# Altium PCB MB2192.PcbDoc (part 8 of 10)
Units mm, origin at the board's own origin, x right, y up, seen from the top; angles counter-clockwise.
Board outline 127 x 97 mm, 6 copper layers (Top Layer, Signal Layer 1, Signal Layer 2, Signal Layer 3, Signal Layer 4, Bottom Layer), stack 1.557 mm thick; 560 components, 463 nets, 2347 pads, 1688 vias.
Unrouted connection lines stored in the file: 3.

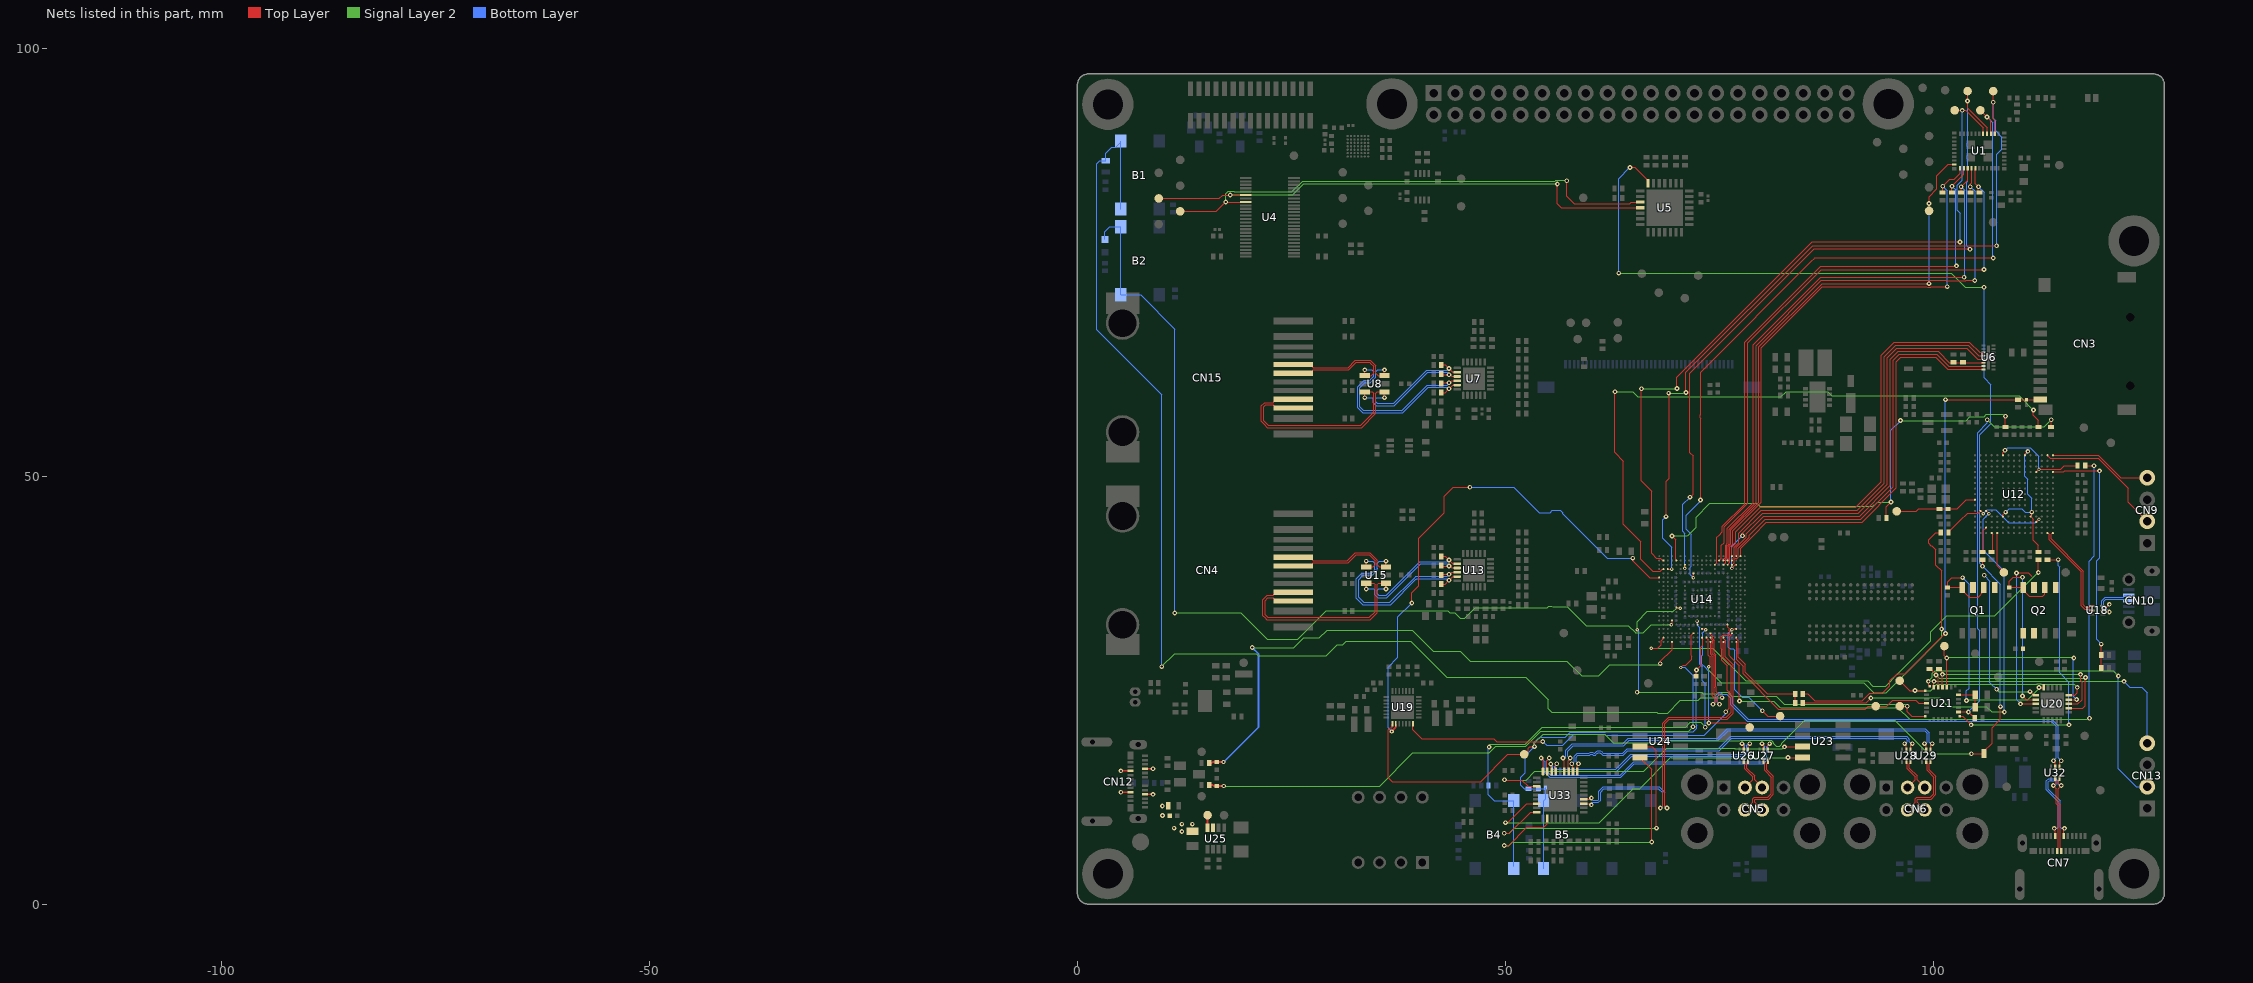
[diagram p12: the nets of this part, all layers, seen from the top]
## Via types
v1: diameter 0.55, hole 0.25, Top Layer to Bottom Layer, 1314 vias
v2: diameter 0.4, hole 0.2, Top Layer to Bottom Layer, 263 vias
v3: diameter 0.5, hole 0.2, Top Layer to Bottom Layer, 51 vias
v4: diameter 0.26, hole 0.1, Top Layer to Signal Layer 1, tented both sides, 29 vias
v5: diameter 0.4, hole 0.2, Top Layer to Bottom Layer, tented both sides, 19 vias
v6: diameter 0.5, hole 0.25, Top Layer to Bottom Layer, 12 vias

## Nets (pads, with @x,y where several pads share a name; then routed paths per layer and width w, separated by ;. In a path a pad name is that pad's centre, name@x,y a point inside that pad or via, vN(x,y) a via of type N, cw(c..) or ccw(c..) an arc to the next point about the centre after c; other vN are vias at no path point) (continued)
NRST: B5.1 B5.2 C118.1 C223.2 D4.2 R88.2 R180.1 TP29.1 U5.14 U14.Y11 U19.1 U37.1 | length 249.9
  Top Layer w0.075: 72.7,27.725 72.85,27.875 72.85,30.019 73.059,30.229 73.059,30.923 72.999,30.983 72.999,31.126 U14.Y11@72.975,31.15
  Top Layer w0.1: U19.1@36.8,21.1 36.8,20.684 36.741,20.625 36.525,20.625 36.3,20.4 36.3,14.781 36.756,14.325 47.125,14.325 50.3,17.5 TP29.1@52.15,17.5 ; TP29.1@52.2,17.5 52.65,17.95 52.65,18.225 52.825,18.4 v1(53.4,18.4) v1@53.425,18.4 ; v1(64.55,86.075) 65.1,86.075 66.675,84.5 U5.14@66.675,84.225 ; C118.1@72.325,26.625 v1(72.325,27.35) 72.7,27.725 ; v1(104.45,17.575) 105.92,17.575 105.92,17.845 106.875,18.8 106.875,20.6 107.85,21.575 v1(107.85,23.075) ; v1(105.75,39.475) R88.2@105.75,40.25
  Signal Layer 2 w0.1: v1@53.4,18.425 53.4,18.85 54.4,19.85 61.625,19.85 62.625,18.85 67.775,18.85 68.025,19.1 77.399,19.1 77.474,19.175 81.051,19.175 81.3,18.926 81.3,18.804 81.678,18.426 82.03,18.426 82.279,18.675 82.279,18.784 84.97,21.475 95.5,21.475 99.4,17.575 v1(104.45,17.575) ; v1(63.25,73.725) 102.075,73.725 103.725,72.075 v1(105.925,72.075)
  Bottom Layer w0.1: B5.2@54.475,4.15 B5.1@54.475,12.1 54.692,12.317 U37.1@54.692,13.602 ; U37.1@54.692,13.625 U37.1@54.692,13.602 ; v1(63.25,73.725) 63.25,84.775 v1(64.55,86.075) ; v1(72.325,27.35) 72.325,23.759 72.3,23.734 72.3,20.951 72.35,20.901 72.35,20.549 72.3,20.499 72.3,20.475 71.975,20.15 61.725,20.15 61.65,20.075 57.6,20.075 57.025,19.5 54.025,19.5 53.4,18.875 v1(53.4,18.4) 52.349,17.349 52.349,15.349 51.8,14.8 51.8,13.9 52.213,13.487 R180.1@52.692,13.487 C223.2@53.867,13.487 54.577,13.487 U37.1@54.692,13.602 ; v1(105.925,72.075) 105.925,61.5 106.725,60.7 106.725,56.15 105.422,54.847 105.422,39.803 v1(105.75,39.475) 107.85,37.375 v1(107.85,23.075)
PA13: B2.1 B2.2 LD4.2 U14.T4 | length 115.8
  Top Layer w0.09: v2@69.475,32.725 U14.T4@69.475,33.15
  Signal Layer 2 w0.09: 65.175,31.75 65.2,31.725 66.125,31.725 67.05,32.65 v2(69.4,32.65)
  Signal Layer 2 w0.1: v1(11.375,34.025) 11.4,34.05 19.075,34.05 22.15,30.975 25.75,30.975 29.05,34.275 43.261,34.275 43.486,34.05 44.058,34.05 44.708,33.4 45.225,33.4 46.475,34.65 54.9,34.65 55.077,34.827 55.429,34.827 55.53,34.725 57.25,34.725 59.425,32.55 64.375,32.55 65.175,31.75
  Bottom Layer w0.1: LD4.2@3.205,77.663 3.205,78.58 3.763,79.138 B2.1@5.055,79.138 B2.2@5.055,71.188 7.372,71.188 11.375,67.185 v1(11.375,34.025)
PA14: B1.1 B1.2 LD3.2 U14.W13 | length 154
  Top Layer w0.075: U14.W13@73.975,31.65 73.998,31.627 73.998,31.502 74.225,31.275 74.225,30.987 74.39,30.822 74.39,29.335 74.595,29.13 74.595,27.916 74.608,27.903 74.608,27.725
  Top Layer w0.1: 74.608,27.725 74.608,26.955 74.595,26.942 74.595,25.408 74.613,25.39 74.613,24.837 v1(75.325,24.125)
  Signal Layer 2 w0.1: v1@9.85,27.775 9.875,27.775 11.35,29.25 20.879,29.25 21.129,29 29.058,29 30.358,30.3 30.999,30.3 31.424,30.725 38.925,30.725 43.15,26.5 52.367,26.5 55,23.867 55,22.8 55.4,22.4 67.7,22.4 67.775,22.325 68.95,22.325 70.451,23.826 72.551,23.826 72.85,24.125 v1(75.325,24.125)
  Bottom Layer w0.1: B1.2@5.055,81.213 B1.1@5.055,89.038 ; B1.1@5.055,89.163 B1.1@5.055,89.038 ; v1(9.85,27.75) 9.85,59.525 2.275,67.1 2.275,86.517 2.621,86.863 LD3.2@3.305,86.863 3.305,87.73 4.013,88.438 4.455,88.438 B1.1@5.055,89.038
PF8_WKUP: U14.F1 U19.2 | length 61.8
  Top Layer w0.075: 65.175,39.85 66.875,38.15 U14.F1@67.975,38.15
  Top Layer w0.1: v1(39.075,35.175) 39.075,36.375 39.9,37.2 39.9,42.775 42.875,45.75 42.875,47.642 43.936,48.702 v1(45.852,48.702) ; v1(64.875,40.425) 64.875,40.15 65.175,39.85
  Top Layer w0.15: v3(36.725,20.175) 37.191,20.641 37.191,21.091 U19.2@37.2,21.1
  Bottom Layer w0.1: v3(36.725,20.175) 36.3,20.6 36.3,27.7 37.45,28.85 37.45,33.55 v1(39.075,35.175) ; v1(45.852,48.702) 50.998,48.702 53.95,45.75 55.225,45.75 55.475,46 56.426,46 56.675,45.751 56.675,45.625 61.875,40.425 v1(64.875,40.425)
PH4: R188.2 R189.2 U14.Y19 | length 12.4
  Top Layer w0.075: U14.Y19@76.975,31.15 76.986,31.139 76.986,30.989 77.225,30.75 77.225,30.296 77.225,28.825 77.638,28.412 78.05,28 78.05,27.725
  Top Layer w0.1: 78.05,27.725 78.05,27.1 80.582,24.568 R188.2@83.85,24.568 R189.2@83.85,23.518
PRTPWR1: U23.3 U33.12 | length 40.6
  Top Layer w0.1: v1(49.9,14.525) 49.945,14.5 50.345,14.5 ccw(c50.55,14.873) 50.568,14.448 51.817,14.5 51.9,14.5 51.929,14.471 52.65,13.75 U33.12@53.65,13.75 ; v1(82.604,18.376) 84.666,18.376 84.715,18.425 U23.3@84.725,18.415
  Signal Layer 2 w0.1: v1(49.9,14.525) 49.975,14.45 50.474,14.45 50.535,14.448 ccw(c50.55,14.873) 50.557,14.448 52.429,14.479 53.45,15.5 66.175,15.5 68.875,18.2 76.778,18.2 76.803,18.176 82.326,18.176 82.526,18.376 v1(82.604,18.376)
PRTPWR2: U23.4 U33.16 | length 42.4
  Top Layer w0.1: v1(50.025,9.525) 50.3,9.525 52.525,11.75 U33.16@53.65,11.75 ; v1(83.029,17.126) 84.696,17.126 84.72,17.15 U23.4@84.725,17.145
  Signal Layer 2 w0.1: v1(50.025,9.525) 60.95,9.525 64.925,13.5 65.7,13.5 69.35,17.15 69.374,17.126 v1(83.029,17.126)
PRTPWR3: U24.3 U33.18 | length 34
  Top Layer w0.1: v1(49.875,8.275) 50.475,8.275 52.95,10.75 U33.18@53.65,10.75 ; U24.3@65.725,18.39 67.185,18.39 67.65,17.925 v1(67.65,8.875)
  Signal Layer 2 w0.1: v1(49.875,8.275) 50.425,8.275 51.025,8.875 v1(67.65,8.875)
PRTPWR4: U24.4 U33.20 | length 34.5
  Top Layer w0.1: v1(49.875,6.85) 50.375,6.85 52.525,9 54.5,9 54.9,9.4 U33.20@54.9,10 ; U24.4@65.725,17.12 67.1,15.745 v1(67.1,7.25)
  Signal Layer 2 w0.1: v1(49.875,6.85) 50.375,6.85 50.775,7.25 v1(67.1,7.25)
PWR_LP: TP61.1 U14.V19 | length 15.1
  Top Layer w0.09: v2@76.55,32.15 U14.V19@76.975,32.15
  Top Layer w0.1: v1(80.025,22.6) 80.65,21.975 TP61.1@82.1,21.975 TP61.1@82.475,21.975
  Bottom Layer w0.09: v2(76.475,32.075) 76.059,31.659 76.059,31.462 76.059,30.041 76.275,29.825 76.625,29.825 76.814,29.636 76.814,27.725 76.814,25.061 77.684,24.191 77.7,24.175
  Bottom Layer w0.1: 77.684,24.191 78.434,24.191 v1(80.025,22.6)
PWR_NJTRST: TP63.1 U14.V11 | length 17.2
  Top Layer w0.1: U14.V11@72.975,32.15 v2@73.4,32.15 ; v1(73.775,21.175) 78.025,21.175 TP63.1@78.55,20.65 TP63.1@78.55,20.3
  Bottom Layer w0.09: v2(73.425,32.075) 73.075,31.725 73.075,29.125 72.95,29 72.95,28.05 73.275,27.725 73.775,27.225 73.775,26.55
  Bottom Layer w0.1: v1(73.775,21.175) 73.775,26.55
PWR_ON: U14.U17 U19.7 | length 51.6
  Top Layer w0.075: 75.284,31.308 75.228,31.252 75.228,29.837 75.284,29.781 75.284,28.516 75.95,27.85 75.95,27.725 ; 75.284,31.309 75.378,31.403 76.076,31.403 76.225,31.552 76.225,31.856 76.144,31.938 76.144,32.206 75.974,32.376 U14.U17@75.974,32.65
  Top Layer w0.1: U19.7@39.2,21.1 39.2,20.35 40.225,19.325 48.662,19.325 48.987,19 v1(54.375,19) ; v1(75.75,22.475) 76.15,22.875 76.15,24.816 75.95,25.016 75.95,27.725
  Bottom Layer w0.1: v1(54.375,19) 54.825,18.55 56.7,18.55 58,19.85 61.625,19.85 61.75,19.725 73.225,19.725 75.75,22.25 v1(75.75,22.475)
PWR_ON_DB: C102.2 Q2.5 Q2.6
RD1_N: CN4.8 R97.1 U13.22 U15.6 | length 34
  Top Layer w0.09: CN4.8@25.2,40.53 27.195,40.53 27.58,40.145 29.93,40.145 31.531,40.145 32.446,41.06 34.169,41.06 35.025,40.204 35.025,39.625 35.25,39.4 U15.6@36.05,39.4 v1(36.05,40.075) ; R97.1@42.525,38.475 42.6,38.55 v1(43.425,38.55) 43.5,38.55 43.725,38.775 U13.22@44.375,38.775
  Bottom Layer w0.09: v1(36.05,40.075) 35.275,40.075 35.025,39.825 35.025,39.218 35.035,39.208 35.035,38.992 34.443,38.4 33.339,38.4 32.864,37.925 32.85,37.925 32.85,35.839 33.425,35.264 33.425,35.25 36.486,35.25 39.444,38.208 39.458,38.208 39.531,38.281 43.231,38.281 43.425,38.475 v1(43.425,38.55)
RD1_P: CN4.7 R99.1 U13.23 U15.1 | length 34.1
  Top Layer w0.09: CN4.7@25.2,39.51 27.195,39.51 27.57,39.885 29.822,39.885 31.639,39.885 32.554,40.8 34.075,40.8 34.775,40.1 34.775,39.625 34.55,39.4 U15.1@33.75,39.4 v1(33.75,40.075) ; R99.1@42.525,37.4 42.975,37.4 v1(43.413,37.838) 43.85,38.275 U13.23@44.375,38.275
  Bottom Layer w0.09: v1(33.75,40.075) 34.525,40.075 34.765,39.835 34.765,39.11 34.775,39.1 34.335,38.66 33.231,38.66 32.756,38.185 32.742,38.185 32.59,38.033 32.59,35.731 33.165,35.156 33.165,35.142 33.317,34.99 36.594,34.99 39.552,37.948 39.566,37.948 39.639,38.021 43.229,38.021 v1(43.413,37.838)
RD2_N: CN15.8 R40.1 U7.22 U8.6 | length 33.5
  Top Layer w0.09: CN15.8@25.2,63.06 27.195,63.06 27.455,62.8 27.455,62.795 27.565,62.685 31.621,62.685 32.486,63.55 34.229,63.55 34.85,62.929 34.85,62.05 35.15,61.75 U8.6@35.875,61.75 v1(35.875,62.425) ; R40.1@42.525,60.85 42.6,60.925 v1(43.425,60.925) 43.5,60.925 43.725,61.15 U7.22@44.375,61.15
  Bottom Layer w0.09: v1(35.875,62.425) 35.075,62.425 34.86,62.21 34.86,61.581 34.385,61.106 34.385,61.092 34.233,60.94 33.61,60.94 33.6,60.95 33.01,60.36 33.01,58.11 33,58.1 33.415,57.685 37.89,57.685 37.9,57.675 40.881,60.656 43.231,60.656 43.425,60.85 v1(43.425,60.925)
RD2_P: CN15.7 R42.1 U7.23 U8.1 | length 33.6
  Top Layer w0.09: CN15.7@25.2,62.04 27.195,62.04 27.455,62.3 27.455,62.305 27.575,62.425 31.729,62.425 32.604,63.3 34.125,63.3 34.225,63.2 34.6,62.825 34.6,62.05 34.3,61.75 U8.1@33.575,61.75 v1(33.575,62.425) ; R42.1@42.525,59.775 42.975,59.775 v1(43.413,60.213) 43.85,60.65 U7.23@44.375,60.65
  Bottom Layer w0.09: v1(33.575,62.425) 34.375,62.425 34.6,62.2 34.6,61.689 34.125,61.214 34.125,61.2 33.718,61.2 33.708,61.21 33.492,61.21 32.75,60.468 32.75,58.218 32.74,58.208 32.74,57.992 33.307,57.425 37.782,57.425 37.792,57.415 38.008,57.415 40.989,60.396 43.229,60.396 v1(43.413,60.213)
SDMMC1_CK: R33.2 R34.1 U6.6 U14.A19 | length 48.9
  Top Layer w0.075: U14.A19@76.975,40.65 76.975,41.7 78.15,42.875 78.15,43.125
  Top Layer w0.1: 78.15,43.125 78.15,43.265 80.21,45.325 91.385,45.325 94.975,48.915 94.975,63.69 95.885,64.6 100.565,64.6 101.89,63.275 U6.6@105.875,63.275
SDMMC1_CMD: U6.5 U14.C19 | length 51.6
  Top Layer w0.09: v1(77.7,43.05) v1@77.7,43.125
  Top Layer w0.1: v2(76.475,39.225) 76.875,39.625 76.95,39.625 76.975,39.65 U14.C19@76.975,39.638 ; v1@77.7,43.125 77.7,43.31 80.065,45.675 91.24,45.675 94.625,49.06 94.625,63.835 95.74,64.95 103.935,64.95 105.21,63.675 U6.5@105.875,63.675
  Bottom Layer w0.09: v2(76.475,39.225) 76.475,41.825 v1(77.7,43.05)
SDMMC1_D0: U6.7 U14.C18 | length 49.8
  Top Layer w0.075: U14.C18@76.475,39.65 76.725,39.9 76.725,40.275 76.85,40.4 77.079,40.4 77.225,40.546 77.225,41.605 78.505,42.885 78.505,43.125
  Top Layer w0.1: 78.505,43.125 80.355,44.975 91.53,44.975 95.325,48.77 95.325,63.545 96.03,64.25 100.42,64.25 101.795,62.875 U6.7@105.875,62.875
SDMMC1_D1: U6.8 U14.A20 | length 47.8
  Top Layer w0.075: U14.A20@77.475,40.65 77.475,41.6 79,43.125
  Top Layer w0.1: 79,43.125 80.5,44.625 91.675,44.625 95.675,48.625 95.675,63.4 96.175,63.9 100.275,63.9 101.7,62.475 U6.8@105.875,62.475
SDMMC1_D2: U6.3 U14.A18 | length 50.3
  Top Layer w0.075: U14.A18@76.475,40.65 76.475,41.716 76.9,42.141 76.9,43.125
  Top Layer w0.1: 76.9,43.125 76.9,43.5 79.775,46.375 90.95,46.375 93.925,49.35 93.925,64.15 95.425,65.65 104.225,65.65 105.4,64.475 U6.3@105.875,64.475
SDMMC1_D3: U6.4 U14.B18 | length 50.4
  Top Layer w0.075: U14.B18@76.475,40.15 76.475,40.296 76.725,40.546 76.725,41.705 77.25,42.23 77.25,43.125
  Top Layer w0.1: 77.25,43.125 77.25,43.355 79.92,46.025 91.095,46.025 94.275,49.205 94.275,63.98 95.595,65.3 104.08,65.3 105.305,64.075 U6.4@105.875,64.075
SDMMC2_CK: TP27.1 U1.20 U14.B17 | length 65.9
  Top Layer w0.075: U14.B17@75.975,40.15 75.987,40.162 75.987,40.309 76.059,40.381 76.059,41.798 76.35,42.089 76.35,43.125
  Top Layer w0.1: 76.35,43.125 76.35,43.733 79.6,46.983 79.6,65.1 87,72.5 v1(99.5,72.5) ; TP27.1@99.5,81 v1(99.5,81.875) 99.5,82.675 100.425,83.6 100.425,85.125 101.725,86.425 U1.20@102.45,86.425
  Bottom Layer w0.1: v1(99.5,72.5) v1(99.5,81.875)
SDMMC2_CMD: R14.2 U1.22 U14.C17 | length 67.6
  Top Layer w0.075: U14.C17@75.975,39.65 75.975,39.678 76.228,39.931 76.228,40.311 76.228,41.728 76.55,42.05 76.55,42.35 76.55,43.125
  Top Layer w0.1: 76.55,43.125 76.55,43.65 79.875,46.975 79.875,65 87.025,72.15 99.249,72.15 99.324,72.075 99.676,72.075 99.751,72.15 v1(101.625,72.15) ; R14.2@101.1,83.15 v1(101.1,83.875) 101.95,84.725 102.45,84.725 103.125,85.4 U1.22@103.125,85.975
  Bottom Layer w0.1: v1(101.1,83.875) 101.625,83.35 v1(101.625,72.15)
SDMMC2_D0: R16.2 U1.24 U14.B16 | length 68.5
  Top Layer w0.075: U14.B16@75.475,40.15 75.498,40.173 75.498,40.298 75.721,40.521 75.721,41.521 75.721,41.938 75.95,42.167 75.95,43.125
  Top Layer w0.1: 75.95,43.125 75.95,43.9 78.975,46.925 78.975,65.35 86.875,73.25 v1(103.6,73.25) ; R16.2@103.25,83.15 v1(103.25,83.825) 104.025,84.6 U1.24@104.025,85.975
  Bottom Layer w0.1: v1(103.25,83.825) 103.675,83.4 103.675,73.325 v1(103.6,73.25)
SDMMC2_D1: R18.2 U1.26 U14.B15 | length 70.9
  Top Layer w0.075: U14.B15@74.975,40.15 75.225,40.4 75.225,41.025 75.225,41.92 75.55,42.245 75.55,43.125
  Top Layer w0.1: 75.55,43.125 75.55,44.066 78.325,46.841 78.325,65.575 86.9,74.15 v1(105.925,74.15) ; U1.26@104.925,85.975 104.925,84.15 105.25,83.825 v1(105.275,83.825) 105.275,83.275 R18.2@105.4,83.15
  Bottom Layer w0.1: v1(105.275,83.825) 105.275,83.8 105.925,83.15 v1(105.925,74.15)
SDMMC2_D2: R15.2 U1.23 U14.C14 | length 68.8
  Top Layer w0.075: U14.C14@74.475,39.65 74.725,39.9 74.725,42.875 74.975,43.125
  Top Layer w0.1: 74.975,43.125 75.35,43.5 75.35,44.149 77.95,46.749 77.95,65.675 86.825,74.55 102.675,74.55 v1(102.7,74.575) ; R15.2@102.175,83.15 v1(102.175,83.875) 103.575,85.275 U1.23@103.575,85.975
  Bottom Layer w0.1: v1(102.175,83.875) 102.6,83.45 102.6,74.797 102.7,74.697 v1(102.7,74.575)
SDMMC2_D3: R17.2 U1.25 U14.C16 | length 70.1
  Top Layer w0.075: U14.C16@75.475,39.65 75.721,39.896 75.721,40.282 75.89,40.451 75.89,41.69 75.89,41.868 76.15,42.128 76.15,43.125
  Top Layer w0.1: 76.15,43.125 76.15,43.816 79.3,46.966 79.3,65.25 86.925,72.875 99.274,72.875 99.324,72.925 101.5,72.925 101.6,72.825 103.776,72.825 103.826,72.875 v1(104.85,72.875) ; R17.2@104.325,83.15 v1(104.325,83.825) 104.325,84.125 104.475,84.275 U1.25@104.475,85.975
  Bottom Layer w0.1: v1(104.325,83.825) 104.875,83.275 104.875,72.9 v1(104.85,72.875)
SNK_GDCG: C87.1 Q2.2 Q2.4 U20.7 | length 23.8
  Top Layer w0.1: v1(110.425,24.325) 110.85,23.9 U20.7@111.975,23.9 ; v1(110.425,38.2) 109.35,38.2 108.875,37.725 C87.1@108.875,37 Q2.4@110.495,37 110.495,36.655 111.2,35.95 112.775,35.95 113.035,36.21 Q2.2@113.035,37
  Bottom Layer w0.1: v1(110.425,24.325) v1(110.425,38.2)
SNK_GDCS: Q2.1 Q2.3 U20.8 | length 19.2
  Top Layer w0.1: v1(109.725,38.7) 111.075,38.7 111.475,38.3 ; v1(110.2,23.4) U20.8@111.975,23.4
  Bottom Layer w0.1: v1(109.725,38.7) 109.725,23.875 v1(110.2,23.4)
SRC_GDCG: C86.1 Q1.2 Q1.4 U20.5 | length 32.7
  Top Layer w0.1: v1(103.425,38.15) 102.15,38.15 101.675,37.675 C86.1@101.675,37 Q1.4@103.37,37 103.37,36.68 104.175,35.875 105.225,35.875 105.91,36.56 Q1.2@105.91,37 ; v1(112.35,25.3) 112.875,25.3 U20.5@112.9,25.325
  Signal Layer 2 w0.1: v1(103.875,23.8) 103.95,23.875 111.05,23.875 112.212,25.037 112.212,25.04 112.35,25.178 v1(112.35,25.3)
  Bottom Layer w0.1: v1(103.425,38.15) 104.175,37.4 104.175,25.225 103.875,24.925 v1(103.875,23.8)
SRC_GDCS: Q1.1 Q1.3 U20.6 | length 18.8
  Top Layer w0.1: v1(111.3,24.825) 111.725,24.4 U20.6@111.975,24.4
  Signal Layer 2 w0.1: v1(107.4,25.1) 107.675,24.825 v1(111.3,24.825)
  Bottom Layer w0.1: v1(105.95,38.425) 106.625,37.75 106.625,25.875 v1(107.4,25.1)
STLINK_SWCLK: R90.2 U14.Y2 | length 57
  Top Layer w0.075: v2(67.05,29.9) 67.8,29.9 68.225,30.325 68.225,30.76 68.475,31.01 U14.Y2@68.475,31.15
  Top Layer w0.1: v1(112.275,38.75) R90.2@112.275,40.25
  Signal Layer 2 w0.1: v2(67.05,29.9) 74.246,29.9 78.071,26.075 91.025,26.075 92.325,26.075 92.925,25.475 94.425,25.475 95.925,26.975 99.725,30.775 99.725,31.83 101.57,33.675 107.2,33.675 v1(112.275,38.75)
STLINK_SWDIO: R81.2 U14.Y12 | length 48.9
  Top Layer w0.075: U14.Y12@73.475,31.15 73.725,30.9 73.725,29.1 73.925,28.9 73.925,27.956 73.775,27.806 v2(73.775,27.75)
  Top Layer w0.1: R81.2@100.875,43.4 100.3,43.4 99.45,42.55 99.45,42.149 99.699,41.9 99.799,41.9 100.3,41.399 100.3,39.6 100.975,38.925 v1(100.975,32.15)
  Signal Layer 2 w0.09: v2@73.775,27.725 v2(73.775,27.75)
  Signal Layer 2 w0.1: v2@73.775,27.725 73.775,27.3 75.225,25.85 78.175,25.85 91.025,25.85 91.9,25.85 93.025,24.725 94.525,24.725 100.975,31.175 v1(100.975,32.15)
STLINK_SWO: R61.2 U14.W18 | length 81.2
  Top Layer w0.075: 76.213,28.988 76.144,29.058 76.144,30.744 76.225,30.825 76.225,31.3 76.445,31.52 76.445,31.62 U14.W18@76.474,31.65 ; 76.214,28.989 77.35,27.853 77.35,27.725
  Top Layer w0.1: v1(77.35,23.725) 77.35,27.725 ; R61.2@117.75,51.225 v1(118.775,51.225)
  Signal Layer 2 w0.1: v1(77.35,23.725) 80.3,23.725 81.375,23.725 82.075,23.025 82.15,22.95 95.85,22.95 97.225,21.575 117.978,21.575 118.128,21.725 v1(118.25,21.725)
  Bottom Layer w0.1: v1(118.25,21.725) 118.2,21.775 118.2,40.075 118.825,40.7 118.825,51.175 v1(118.775,51.225)
STLK_LED: R117.2 R125.2 U12.D15 | length 28.9
  Top Layer w0.1: U12.D15@113.975,50.5 115.225,50.5 115.35,50.625 v1(119.425,50.625) ; R125.2@119.625,27.6 R117.2@119.625,29.1 v1(119.625,30.375)
  Bottom Layer w0.1: v1(119.425,50.625) 119.425,40.45 119.075,40.1 119.075,30.925 v1(119.625,30.375)
STLK_RST: C65.2 R68.1 TP44.1 U12.J1 | length 9.7
  Top Layer w0.1: TP44.1@95.725,45.9 98,45.9 98.275,46.175 99.65,46.175 R68.1@100.725,46.175 C65.2@101.725,46.175 102.8,46.175 103.875,47.25 U12.J1@104.875,47.25
STLK_SWCLK: CN9.2 U12.A14 | length 15.9
  Top Layer w0.1: U12.A14@113.325,52.45 113.65,52.125 119.275,52.125 122.8,48.6 122.8,46.93 CN9.2@125,44.73
STLK_SWDIO: CN9.4 U12.A15 | length 12.1
  Top Layer w0.1: U12.A15@113.975,52.45 119.275,52.45 121.915,49.81 CN9.4@125,49.81
STLK_VCP2_RX: R91.1 U21.8 | length 34.3
  Top Layer w0.1: U21.8@103.075,21.95 103.425,21.95 v1(104.425,20.95) ; R91.1@113.35,40.25 v1(114.6,40.25)
  Signal Layer 2 w0.1: v1(104.425,20.95) v1(115.85,20.95)
  Bottom Layer w0.1: v1(114.6,40.25) 114.6,39.56 114.751,39.409 114.751,27.049 115.85,25.95 v1(115.85,20.95)
STLK_VCP2_TX: R56.1 R187.1 U21.9 | length 46.5
  Top Layer w0.1: U21.9@102.95,22.45 v1(104.1,22.45) 104.475,22.075 104.645,22.075 104.85,21.87 R187.1@104.85,21.775 ; R56.1@113.775,55.75 v1(113.775,56.6)
  Signal Layer 2 w0.1: v1(106.3,56.6) 107.125,55.775 112.95,55.775 v1(113.775,56.6)
  Bottom Layer w0.1: v1(104.1,22.45) 105.429,23.779 105.429,31.942 105.175,32.196 105.175,55.1 106.3,56.225 v1(106.3,56.6)
STM32G0_I2C2_SCL: R121.2 U20.18 U21.18 | length 23.3
  Top Layer w0.1: R121.2@100.65,27.475 100.725,27.475 101.075,27.125 v1(101.075,26.85) U21.18@101.075,25.325 ; U20.18@115.825,23.4 116.875,23.4 117.375,23.9 117.375,25.925 117.2,26.1 v1(117.2,26.85)
  Signal Layer 2 w0.1: v1(101.075,26.85) v1(117.2,26.85)
STM32G0_I2C2_SDA: R120.1 U20.17 U21.19 | length 25.6
  Top Layer w0.1: R120.1@99.575,27.475 99.625,27.475 v1(100.325,26.775) 100.575,26.525 U21.19@100.575,25.325 ; U20.17@115.825,22.9 117.475,22.9 117.775,23.2 v1(117.775,26.475)
  Signal Layer 2 w0.1: v1(100.325,26.775) 100.7,26.4 117.7,26.4 v1(117.775,26.475)
STM32G0_INTN: TP59.1 U14.N5 U21.28 | length 50.8
  Top Layer w0.09: U14.N5@69.975,34.65 70.002,34.623 70.397,34.623 v2(70.442,34.578)
  Top Layer w0.1: TP59.1@96.075,23.125 v1(96.95,23.125) 96.95,22.5 97.5,21.95 U21.28@99.075,21.95
  Signal Layer 2 w0.09: v2(65.4,32.075) 65.4,33 66.6,34.2 69.625,34.2 70.003,34.578 v2(70.442,34.578)
  Signal Layer 2 w0.1: v1(65.4,24.75) 72.925,24.75 73.065,24.61 75.28,24.61 75.42,24.75 76.075,24.75 76.525,24.3 81.638,24.3 82.588,23.35 89.75,23.35 96.666,23.35 96.891,23.125 v1(96.95,23.125)
  Bottom Layer w0.09: v2(65.4,32.075) 65.4,32.031 65.57,31.861 65.57,27.725
  Bottom Layer w0.1: v1(65.4,24.75) 65.4,24.869 65.57,25.039 65.57,27.725
STM32G0_SWCLK: CN13.2 U21.21 | length 39
  Top Layer w0.1: v1(99.425,26.025) 99.478,25.972 99.478,25.547 U21.21@99.575,25.45
  Signal Layer 2 w0.1: v1(99.425,26.025) 99.9,26.5 99.9,26.951 100.224,27.275 115.78,27.275 115.805,27.25 116.095,27.25 116.12,27.275 121,27.275 v1(121.625,26.65)
  Bottom Layer w0.1: v1(121.625,26.65) 121.625,15.825 123.72,13.73 CN13.2@125,13.73
STM32G0_SWDIO: CN13.4 U21.20 | length 32.1
  Top Layer w0.1: U21.20@100.075,25.325 v1(100.075,26.025)
  Signal Layer 2 w0.1: v1(100.075,26.025) v1(122.275,26.025)
  Bottom Layer w0.1: v1(122.275,26.025) 122.975,25.325 124.351,25.325 125,24.676 CN13.4@125,18.81
STM32G0_WAKE: TP58.1 U14.AA19 U21.25 | length 27.8
  Top Layer w0.075: U14.AA19@76.974,30.65 76.974,30.61 77.056,30.528 77.056,30.465 77.056,28.543 77.638,27.961 77.775,27.824 77.775,27.725
  Top Layer w0.1: 77.775,27.725 77.775,26.9 81.9,22.775 92.05,22.775 92.4,23.125 TP58.1@93.275,23.125 94.575,23.125 95.25,23.8 97.975,23.8 98.325,23.45 U21.25@99.2,23.45
STMIPI_ERROR: TP25.1 U4.6 U5.18 | length 61.5
  Top Layer w0.1: TP25.1@9.5,82.45 16.575,82.45 16.975,82.85 v1@17.975,82.85 ; v1(17.85,82.85) 17.9,82.9 19.6,82.9 U4.6@19.65,82.85 ; v1(56.075,84.15) 56.075,81.825 56.525,81.375 U5.18@65.775,81.375
  Signal Layer 2 w0.1: v1(17.85,82.85) 17.875,82.875 25.175,82.875 26.45,84.15 v1(56.075,84.15)
STMIPI_INT: TP28.1 U4.8 U5.17 | length 60.5
  Top Layer w0.1: TP28.1@12,80.95 16.225,80.95 v1(17.325,82.05) 17.35,82.025 19.625,82.025 U4.8@19.65,82.05 ; v1(57.175,84.525) 57.175,82.7 58.025,81.85 64.525,81.85 64.7,82.025 U5.17@65.775,82.025
  Signal Layer 2 w0.1: v1(17.325,82.05) 17.325,83 17.6,83.275 18.274,83.275 18.324,83.225 25.05,83.225 26.3,84.475 55.799,84.475 55.899,84.575 57.125,84.575 v1(57.175,84.525)
T_JTDI: R189.1 U12.L3 | length 49.4
  Top Layer w0.1: R189.1@84.75,23.518 92.143,23.518 v1(92.7,24.075) ; U12.L3@106.175,45.95 v2(106.5,45.625)
  Signal Layer 2 w0.1: v1(92.7,24.075) 92.75,24.125 100.725,24.125 101.775,23.075 106.2,23.075 106.822,22.453 v1(108.303,22.453)
  Bottom Layer w0.1: v2(106.5,45.625) 105.85,44.975 105.85,41.375 108.303,38.922 v1(108.303,22.453)
T_NRST: R88.1 U12.P3 | length 3
  Top Layer w0.1: R88.1@105.75,41.15 105.85,41.25 105.85,43.675 U12.P3@106.175,44
T_PWR_EN: TP47.1 U12.R5 | length 4.9
  Top Layer w0.1: U12.R5@107.475,43.35 107.475,39.525 TP47.1@108.25,38.75
T_PWR_EXT: R89.2 U12.R4 | length 2.3
  Top Layer w0.1: R89.2@106.825,41.15 106.925,41.25 106.925,43.216 106.825,43.316 U12.R4@106.825,43.35
T_SWCLK: R90.1 U12.A10 U12.M6 U12.M11 | length 17.3
  Top Layer w0.1: U12.M6@108.125,45.3 108.132,45.307 108.132,45.482 v1(108.45,45.8) ; U12.A10@110.725,52.45 110.754,52.479 110.754,52.604 v1(111.05,52.9) ; v1(111.5,45.8) 111.5,45.425 U12.M11@111.375,45.3 111.7,44.975 111.7,42.5 112.275,41.925 R90.1@112.275,41.15
  Bottom Layer w0.1: v1(108.45,45.8) 108.85,46.2 110.35,46.2 110.763,45.787 111.087,45.787 111.1,45.8 v1(111.5,45.8) 111.5,47.425 111.05,47.875 111.05,49.649 110.7,49.999 110.7,52.428 111.05,52.778 v1(111.05,52.9)
T_SWDIO: R81.1 U12.L2 U12.N12 | length 13.3
  Top Layer w0.1: R81.1@101.775,43.4 101.775,43.475 102.9,44.6 ; 102.901,44.6 103.15,44.849 ; 103.15,44.85 104,45.7 104.736,45.7 104.761,45.675 105.25,45.675 U12.L2@105.525,45.95 v2(105.85,45.625) ; U12.N12@112.025,44.65 v2(112.35,44.975)
  Bottom Layer w0.1: v2(105.85,45.625) 106.295,46.07 107.28,46.07 108.805,44.545 111.92,44.545 v2(112.35,44.975)
T_SWO: R61.1 U12.A6 U12.D12 | length 11.8
  Top Layer w0.1: U12.A6@108.125,52.45 108.125,52.757 108.375,53.007 v1(108.375,53.025) ; U12.D12@112.025,50.5 v2(112.35,50.825) 114.875,50.825 115.275,51.225 R61.1@116.85,51.225
  Bottom Layer w0.1: v1(108.375,53.025) 108.688,53.338 111.337,53.338 112.35,52.325 v2(112.35,50.825)
TAMP_BTN: B4.1 B4.2 R181.1 U14.U10 | length 56.6
  Top Layer w0.09: v2(72.4,33.075) 72.4,32.991 72.475,32.916 U14.U10@72.475,32.65
  Signal Layer 2 w0.1: v1@48.1,18.35 48.066,18.384 48.066,18.466 48.301,18.701 52.326,18.701 54.3,20.675 71.075,20.675 71.625,21.225 72.8,21.225 v1(73.35,20.675)
  Bottom Layer w0.09: v2(72.4,33.075) 72.4,32.613 72.734,32.279 72.734,31.91 72.725,31.901 72.725,28 73,27.725 73,26.125 73.35,25.775
  Bottom Layer w0.1: v1(48.101,18.349) 48.025,18.274 48.025,12.8 48.725,12.1 B4.2@50.975,12.1 B4.1@50.975,4.405 ; v1(73.35,20.675) 73.35,25.775
TD1_N: CN4.4 R92.1 U13.20 U15.4 | length 38.6
  Top Layer w0.09: CN4.4@25.2,36.45 23.205,36.45 22.945,36.19 22.945,36.123 22.892,36.07 22.784,36.07 22.152,36.07 21.665,35.583 21.665,33.717 21.891,33.491 22.142,33.24 34.208,33.24 35.03,34.062 35.03,37.35 35.18,37.5 U15.4@36.05,37.5 v1(36.05,36.825) ; R92.1@42.525,40.65 42.975,40.65 v1(43.413,40.213) 43.85,39.775 U13.20@44.375,39.775
  Bottom Layer w0.09: v1(36.05,36.825) 35.2,36.825 35.025,36.65 35.025,36.264 35.2,36.089 35.2,36.075 36.061,36.075 40.015,40.029 43.229,40.029 v1(43.413,40.213)
TD1_P: CN4.3 R95.1 U13.21 U15.3 | length 37.6
  Top Layer w0.09: CN4.3@25.2,35.43 23.205,35.43 22.945,35.69 22.945,35.757 22.892,35.81 22.676,35.81 22.26,35.81 21.925,35.475 21.925,33.825 22.25,33.5 34.1,33.5 34.77,34.17 34.77,37.35 34.62,37.5 U15.3@33.75,37.5 v1(33.75,36.825) ; R95.1@42.525,39.575 42.6,39.5 v1(43.425,39.5) 43.5,39.5 43.725,39.275 U13.21@44.375,39.275
  Bottom Layer w0.09: v1(33.75,36.825) 34.6,36.825 34.765,36.66 34.765,36.156 34.94,35.981 34.94,35.967 35.092,35.815 36.169,35.815 40.122,39.769 43.231,39.769 43.425,39.575 v1(43.425,39.5)
TD2_N: CN15.4 R37.1 U7.20 U8.4 | length 38.3
  Top Layer w0.09: CN15.4@25.2,58.98 23.205,58.98 22.945,58.72 22.945,58.653 22.892,58.6 22.784,58.6 21.882,58.6 21.49,58.208 21.49,56.392 21.741,56.141 22.192,55.69 33.208,55.69 34.855,57.337 34.855,59.7 35.005,59.85 U8.4@35.875,59.85 v1(35.875,59.175) ; R37.1@42.525,63.025 42.975,63.025 v1(43.413,62.588) 43.85,62.15 U7.20@44.375,62.15
  Bottom Layer w0.09: v1(35.875,59.175) 35,59.175 34.85,59.025 34.85,58.689 35.025,58.514 35.025,58.5 36.936,58.5 40.84,62.404 43.229,62.404 v1(43.413,62.588)
TD2_P: CN15.3 R39.1 U7.21 U8.3 | length 37.3
  Top Layer w0.09: CN15.3@25.2,57.96 23.205,57.96 22.945,58.22 22.945,58.287 22.892,58.34 22.676,58.34 21.99,58.34 21.75,58.1 21.75,56.5 22.3,55.95 33.1,55.95 34.595,57.445 34.595,59.7 34.445,59.85 U8.3@33.575,59.85 v1(33.575,59.175) ; R39.1@42.525,61.95 42.625,61.85 v1(43.425,61.85) 43.525,61.85 43.725,61.65 U7.21@44.375,61.65
  Bottom Layer w0.09: v1(33.575,59.175) 34.45,59.175 34.59,59.035 34.59,58.581 34.765,58.406 34.765,58.392 34.917,58.24 37.044,58.24 40.947,62.144 43.231,62.144 43.425,61.95 v1(43.425,61.85)
UART4_RX: R54.2 R72.1 U14.B5 | length 57.2
  Top Layer w0.075: v1(69.475,43.025) 69.475,43 69.89,42.585 69.89,40.272 69.975,40.187 U14.B5@69.975,40.15
  Top Layer w0.1: R72.1@94.525,45.125 94.525,46.45 v1(95.05,46.975) ; R54.2@108.425,55.75 v1(108.425,57)
  Signal Layer 2 w0.09: v1(69.475,43.025) 71.27,43.025 71.37,43.125
  Signal Layer 2 w0.1: 71.37,43.125 72.3,44.055 72.3,45.225 73.9,46.825 79.387,46.825 79.737,46.475 92.95,46.475 93.45,46.975 v1(95.05,46.975) ; v1(96.175,56.5) 103.825,56.5 104.275,56.95 105.94,56.95 106.215,57.225 108.141,57.225 108.366,57 v1(108.425,57)
  Bottom Layer w0.1: v1(95.05,46.975) 95.05,55.375 v1(96.175,56.5)
UART4_TX: R55.2 U14.D2 | length 76.7
  Top Layer w0.075: 65.175,42.992 65.8,42.367 65.8,40.325 67.221,38.904 68.079,38.904 68.325,39.15 U14.D2@68.475,39.15
  Top Layer w0.1: v1(62.8,59.875) 62.8,52.775 63.8,51.775 63.8,44.367 65.175,42.992 ; v1(111.7,57.725) 111.7,57.125 112.275,56.55 R55.2@112.275,55.75
  Signal Layer 2 w0.1: v1(62.8,59.875) 64.875,59.875 65.472,59.278 82.203,59.278 82.8,59.875 87.65,59.875 88.15,59.375 110.05,59.375 v1(111.7,57.725)
USART2_CTS: TP6.1 U1.5 U14.B2 | length 87.1
  Top Layer w0.075: 67.075,43.125 67.075,40.975 67.65,40.4 68.125,40.4 68.345,40.18 68.445,40.18 U14.B2@68.475,40.15
  Top Layer w0.1: v1(65.9,60.225) 65.85,60.175 65.85,49.45 67.078,48.222 67.078,43.426 67.075,43.423 67.075,43.125 ; v1(70.053,60.253) 70.053,61.55 85.878,77.375 v1(103.125,77.375) ; TP6.1@102.5,92.75 v1(103.375,92.75) 103.775,92.75 105.825,90.7 U1.5@105.825,90.025
  Signal Layer 2 w0.1: v1(65.9,60.225) v1@69.975,60.225
  Bottom Layer w0.1: v1(103.125,77.375) 103.125,80.75 102.8,81.075 102.8,84 103.375,84.575 v1(103.375,92.75)
USART2_RTS: TP3.1 U1.4 U14.C7 | length 86.4
  Top Layer w0.09: v2@70.975,39.15 v2(70.975,39.225) U14.C7@70.975,39.65
  Top Layer w0.1: v1(71.575,47.55) 71.925,47.9 71.925,52.375 71.55,52.75 71.55,62.05 86.075,76.575 104.25,76.575 v1(104.3,76.525) ; TP3.1@104,95 104,92.975 106.275,90.7 U1.4@106.275,90.025
  Bottom Layer w0.09: v2(70.975,39.225) 70.975,43.125
  Bottom Layer w0.1: 70.975,43.125 70.975,43.3 70.725,43.55 70.725,46.7 v1(71.575,47.55) ; v1(104,93.85) 104,88.976 103.95,88.926 103.95,88.574 104,88.524 104,87.476 103.95,87.426 103.95,87.074 104,87.024 104,84.45 103.9,84.35 103.9,76.925 v1(104.3,76.525)
USART2_RX: TP7.1 U1.3 U14.E9 | length 85.5
  Top Layer w0.09: v2(71.975,38.125) U14.E9@71.975,38.65
  Top Layer w0.1: v1(72.8,47.225) 72.8,47.624 72.825,47.649 72.825,48.001 72.825,56.774 72.775,56.824 72.775,57.176 72.8,57.201 72.8,62.15 85.825,75.175 ; 85.825,75.176 86.074,75.425 86.15,75.5 101.924,75.5 101.949,75.525 102.301,75.525 102.326,75.5 v1(107,75.5) ; TP7.1@105.5,92.75 106.725,91.525 U1.3@106.725,90.025
  Bottom Layer w0.075: 71.731,39.494 71.605,39.368 71.605,38.495 v2(71.975,38.125)
  Bottom Layer w0.09: 71.731,39.494 71.731,43.125
  Bottom Layer w0.1: 71.731,43.125 71.731,43.194 71.14,43.785 71.14,45.44 72.662,46.962 72.662,46.965 72.8,47.103 v1(72.8,47.225) ; v1(106.275,91.975) 106.95,91.3 106.95,75.55 v1(107,75.5)
USART2_TX: TP4.1 U1.2 U14.D3 | length 91.1
  Top Layer w0.09: U14.D3@68.975,39.15 v2(69.425,39.15) v2@69.45,39.15
  Top Layer w0.1: v1(68.775,45.275) 68.775,49.425 69.125,49.775 69.125,59.675 v1@69.05,59.75 ; v1(71.103,59.778) 71.103,62.122 71.1,62.125 85.9,76.925 104.099,76.925 104.124,76.95 107.375,76.95 v1(107.4,76.925) ; TP4.1@107,95 v1(107,93.7) 107,91.775 107.175,91.6 U1.2@107.175,90.025
  Signal Layer 2 w0.1: v1(69.078,59.703) 71.047,59.703 71.097,59.753 71.103,59.759 v1(71.103,59.778)
  Bottom Layer w0.09: 68.4,43.125 68.4,42.75 69.425,41.725 v2(69.425,39.15)
  Bottom Layer w0.1: 68.4,43.125 68.4,44.9 v1@68.725,45.225 ; v1(107,93.7) 107,91.825 107.3,91.525 107.3,90.35 108.025,89.625 108.025,88.225 107.4,87.6 v1(107.4,76.925)
USB1CN25_N: CN6.T2 U28.5 | length 3.9
  Top Layer w0.1: U28.5@96.85,16.7 96.85,16.525 96.925,16.45 96.926,16.45 96.985,16.391 96.985,15.79 97.885,14.89 97.885,14.515 CN6.T2@97,13.63
USB1CN25_P: CN6.T3 U28.6 | length 3.9
  Top Layer w0.1: U28.6@97.35,16.7 97.35,16.525 97.275,16.45 97.274,16.45 97.215,16.391 97.215,15.885 98.115,14.985 98.115,14.515 CN6.T3@99,13.63
USB2CN25_N: CN6.B2 U29.5 | length 8.3
  Top Layer w0.1: CN6.B2@97,11.01 97.885,11.895 97.885,12.294 98.091,12.5 99.65,12.5 100.075,12.925 100.075,14.85 99.31,15.615 99.31,16.391 99.251,16.45 99.25,16.45 99.175,16.525 U29.5@99.175,16.7
USB2CN25_P: CN6.B3 U29.6 | length 8.3
  Top Layer w0.1: CN6.B3@99,11.01 98.115,11.895 98.115,12.198 98.187,12.27 99.745,12.27 100.305,12.83 100.305,14.945 99.54,15.71 99.54,16.391 99.599,16.45 99.6,16.45 99.675,16.525 U29.6@99.675,16.7
USB3CN26_N: CN5.T2 U26.5 | length 3.9
  Top Layer w0.1: U26.5@77.85,16.7 77.85,16.525 77.925,16.45 77.926,16.45 77.985,16.391 77.985,15.79 78.885,14.89 78.885,14.515 CN5.T2@78,13.63
USB3CN26_P: CN5.T3 U26.6 | length 3.9
  Top Layer w0.1: U26.6@78.35,16.7 78.35,16.525 78.275,16.45 78.274,16.45 78.215,16.391 78.215,15.885 79.115,14.985 79.115,14.515 CN5.T3@80,13.63
USB4CN26_N: CN5.B2 U27.5 | length 8.3
  Top Layer w0.1: CN5.B2@78,11.01 78.885,11.895 78.885,12.294 79.091,12.5 80.65,12.5 81.075,12.925 81.075,14.85 80.31,15.615 80.31,16.391 80.251,16.45 80.25,16.45 80.175,16.525 U27.5@80.175,16.7
USB4CN26_P: CN5.B3 U27.6 | length 8.3
  Top Layer w0.1: CN5.B3@80,11.01 79.115,11.895 79.115,12.198 79.187,12.27 80.745,12.27 81.305,12.83 81.305,14.945 80.54,15.71 80.54,16.391 80.599,16.45 80.6,16.45 80.675,16.525 U27.6@80.675,16.7
USB_D1_N: U14.AA16 U33.30 | length 40
  Top Layer w0.09: U14.AA16@75.474,30.65 75.475,28.789 76.405,27.859 76.405,27.725 76.4,27.72
  Top Layer w0.1: U33.30@59.15,11.75 59.9,11.75 v1(60.05,11.6) ; v1(68.113,11.238) 68.114,11.238 68.385,11.508 68.385,11.591 68.385,21.16 69.075,21.85 75.825,21.85 76.4,22.425 76.4,27.72
  Bottom Layer w0.1: v1(60.05,11.6) 60.05,11.681 60.161,11.792 60.161,11.826 60.22,11.885 60.303,11.885 60.88,11.885 61.12,12.125 61.12,13.095 61.52,13.495 67.88,13.495 68.385,12.99 68.385,11.512 68.385,11.429 68.194,11.238 v1(68.113,11.238)
USB_D1_P: U14.Y16 U33.31 | length 41
  Top Layer w0.09: U14.Y16@75.474,31.15 75.491,31.134 75.491,30.993 75.728,30.755 75.728,30.545 75.695,30.511 75.695,28.88 76.625,27.95 76.625,27.725 76.63,27.72
  Top Layer w0.1: U33.31@59.15,12.25 59.9,12.25 v1(60.05,12.4) ; v1(68.888,11.238) v1(68.888,11.238) 68.615,11.508 68.615,11.687 68.615,21.065 69.17,21.62 75.92,21.62 76.63,22.33 76.63,27.72
  Bottom Layer w0.1: v1(60.05,12.4) 60.05,12.319 60.161,12.208 60.161,12.174 60.22,12.115 60.398,12.115 60.785,12.115 60.89,12.22 60.89,13.191 61.425,13.725 67.975,13.725 68.615,13.085 68.615,11.607 68.615,11.429 68.806,11.238 v1(68.888,11.238)
USB_D2_N: U14.Y13 U32.2 | length 56.1
  Top Layer w0.075: U14.Y13@73.975,31.15 73.986,31.139 73.986,30.987 74.221,30.752 74.221,30.548 74.18,30.507 74.18,29.27 74.395,29.055 74.395,27.725
  Top Layer w0.1: 74.395,27.725 74.395,25.325 74.413,25.307 74.413,24.438 74.753,24.098 74.753,23.623 v1(75.025,23.35) ; v1(114.05,16.75) 114.25,16.55 U32.2@114.25,16
  Bottom Layer w0.1: v1(75.025,23.35) 74.998,23.35 74.752,23.596 74.752,23.679 74.753,24.253 75.05,24.55 75.875,24.55 76.35,24.075 76.35,23.3 78.255,21.395 113.755,21.395 114.385,20.765 114.385,17.41 114.385,17.085 v1(114.05,16.75)
USB_D2_P: U14.AA13 U32.1 | length 56.2
  Top Layer w0.075: U14.AA13@73.975,30.65 73.975,29.175 74.165,28.985 74.165,27.725
  Top Layer w0.1: 74.165,27.725 74.165,24.677 74.183,24.659 74.183,24.342 74.523,24.003 74.523,23.623 v1(74.25,23.35) ; U32.1@114.75,16 114.75,16.55 v1(114.95,16.75)
  Bottom Layer w0.1: v1(74.25,23.35) 74.277,23.35 74.523,23.596 74.523,23.774 74.523,24.348 74.955,24.78 75.97,24.78 76.58,24.17 76.58,23.395 78.35,21.625 113.85,21.625 114.615,20.86 114.615,17.505 114.615,17.085 v1(114.95,16.75)
USB_DCONN_N: CN7.A7 CN7.B7 U32.5 | length 18.1
  Top Layer w0.1: U32.5@114.25,14.7 114.25,14.525 114.325,14.45 114.326,14.45 114.395,14.381 114.395,14.098 114.147,13.85 v1(114.025,13.85) 114.373,13.502 114.373,13.127 114.373,11.728 114.61,11.49 114.61,8.735 114.61,6.57 114.475,6.435 CN7.B7@114.475,6.235 ; CN7.A7@115.225,7.935 v1@115.225,8.85
  Bottom Layer w0.1: v1(114.025,13.85) 114.111,13.936 114.288,13.936 114.373,14.021 114.373,14.104 114.373,14.271 114.206,14.437 113.587,14.437 113.45,14.3 113.45,13.45 114.84,12.06 114.84,11.123 114.84,9.23 114.84,9 114.959,8.881 115.294,8.881 v1(115.325,8.85)
USB_DCONN_P: CN7.A6 CN7.B6 U32.6 | length 18.8
  Top Layer w0.1: CN7.A6@114.225,7.935 v1@114.225,8.85 ; U32.6@114.75,14.7 114.75,14.525 114.625,14.4 114.625,14.053 114.828,13.85 v1(114.95,13.85) 114.603,13.503 114.603,13.032 114.603,11.823 114.84,11.585 114.84,8.83 114.84,6.57 114.975,6.435 CN7.B6@114.975,6.235
  Bottom Layer w0.1: v1(114.125,8.85) 114.156,8.881 114.491,8.881 114.61,9 114.61,11.218 114.61,11.965 113.22,13.355 113.22,14.395 113.492,14.667 114.302,14.667 114.603,14.367 114.603,14.199 114.603,14.021 114.687,13.936 114.864,13.936 v1(114.95,13.85)
USB_DEV_HS_CN_N: CN10.2 U18.5 | length 6.2
  Top Layer w0.1: U18.5@119.825,34.325 120.375,34.325 v1(120.575,34.125)
  Bottom Layer w0.1: v1(120.575,34.125) 120.575,34.135 120.24,34.47 119.93,34.47 119.67,34.73 119.67,35.47 120.065,35.865 122.166,35.865 122.225,35.924 122.225,35.925 122.375,36.075 CN10.2@122.85,36.075
USB_DEV_HS_CN_P: CN10.3 U18.6 | length 5.4
  Top Layer w0.1: U18.6@119.825,34.825 120.375,34.825 v1(120.575,35.025)
  Bottom Layer w0.1: v1(120.575,35.025) 120.575,35.015 120.26,34.7 120.025,34.7 119.9,34.825 119.9,35.375 120.16,35.635 122.166,35.635 122.225,35.576 122.225,35.575 122.375,35.425 CN10.3@122.85,35.425
USB_DEV_HS_N: U12.R14 U18.2 | length 11.6
  Top Layer w0.1: U12.R14@113.325,43.35 113.354,43.321 113.447,43.321 113.535,43.233 113.535,43.15 113.535,42.59 117.3,38.825 117.3,34.875 117.715,34.46 118.075,34.46 118.216,34.46 118.275,34.401 118.275,34.4 118.35,34.325 U18.2@118.525,34.325
USB_DEV_HS_P: U12.R15 U18.1 | length 11.2
  Top Layer w0.1: U12.R15@113.975,43.35 113.946,43.321 113.853,43.321 113.765,43.233 113.765,43.055 113.765,42.685 117.53,38.92 117.53,34.97 117.81,34.69 117.98,34.69 118.216,34.69 118.275,34.749 118.275,34.75 118.35,34.825 U18.1@118.525,34.825
USB_PWR_CC1: C156.2 R149.1 U14.AA4 | length 71.6
  Top Layer w0.075: v1(68.1,28.1) 68.1,28.375 69.475,29.75 U14.AA4@69.475,30.65
  Top Layer w0.2: R149.1@15.4,16.475 15.425,16.5 15.7,16.5 15.8,16.6 C156.2@16.275,16.6 v6(17.075,16.6)
  Signal Layer 2 w0.09: 65.175,27.975 68.102,27.975 68.1,27.977 v1(68.1,28.1)
  Signal Layer 2 w0.1: v1(20.425,29.975) 25.3,29.975 26.425,31.1 28.275,31.1 29.175,32 39.125,32 41.6,29.525 44.751,29.525 45.876,28.4 57.2,28.4 58.925,26.675 60.899,26.675 62.199,27.975 65.175,27.975
  Bottom Layer w0.2: v6(17.075,16.6) 21.15,20.675 21.15,29.25 v1(20.425,29.975)
USB_PWR_CC2: C151.1 R144.1 U14.W9 | length 72.1
  Top Layer w0.075: v2(70.475,27.65) 70.494,27.65 70.763,27.919 71.101,27.919 71.801,28.618 71.801,28.988 71.728,29.061 71.728,31.403 U14.W9@71.975,31.65
  Top Layer w0.2: R144.1@15.4,13.925 15.8,13.925 15.925,13.8 C151.1@16.275,13.8 v6(17.1,13.8)
  Signal Layer 2 w0.1: v6(17.1,13.8) 35.3,13.8 39.175,17.675 48.1,17.675 48.875,18.45 52.375,18.45 54.125,20.2 71.4,20.2 v1(71.925,20.725)
  Bottom Layer w0.1: v2(70.475,27.65) 70.975,27.65 71.925,26.7 v1@71.925,20.75 ; v1@71.913,20.738 v1(71.925,20.725)
USBC_EN: TP56.1 U20.20 U21.22 | length 24.7
  Top Layer w0.1: TP56.1@96.075,26.1 97.225,24.95 U21.22@99.075,24.95 ; U20.20@115.825,24.4 116.5,24.4 116.825,24.725 v1(116.825,25.325)
  Signal Layer 2 w0.1: v1(97.85,24.95) 99.675,24.95 100.425,25.7 112.149,25.7 112.174,25.725 112.526,25.725 112.551,25.7 116.45,25.7 v1(116.825,25.325)
USBC_INTn: TP51.1 U20.19 U21.17 | length 25.8
  Top Layer w0.1: TP51.1@101.3,30.15 101.3,29.025 v1(101.575,28.75) U21.17@101.575,25.325 ; U20.19@115.825,23.9 v1(116.75,23.9)
  Signal Layer 2 w0.1: v1(101.575,28.75) 101.65,28.825 116.35,28.825 v1(116.425,28.75)
  Bottom Layer w0.1: v1(116.425,28.75) 116.35,28.675 116.35,24.3 v1(116.75,23.9)
USBDN1_N: U28.2 U33.1 | length 43.3
  Top Layer w0.1: U33.1@58.4,15.5 58.4,16.25 v1(58.55,16.4) ; v1(96.65,18.75) 96.85,18.55 U28.2@96.85,18
  Bottom Layer w0.1: v1(58.55,16.4) 58.498,16.4 58.265,16.633 58.265,16.716 58.265,17.19 58.47,17.395 59.866,17.395 cw(c60.075,17.025) 60.284,17.395 60.521,17.395 60.55,17.424 60.623,17.497 60.626,17.5 cw(c60.95,17.225) 61.274,17.5 61.277,17.497 61.28,17.494 61.379,17.395 63.795,17.395 64.32,17.92 74.97,17.92 76.425,19.375 96.775,19.375 96.985,19.165 96.985,18.978 96.757,18.75 v1(96.65,18.75)
USBDN1_P: U28.1 U33.2 | length 44
  Top Layer w0.1: v1(57.75,16.4) 57.9,16.25 U33.2@57.9,15.5 ; U28.1@97.35,18 97.35,18.55 v1(97.55,18.75)
  Bottom Layer w0.1: v1(57.75,16.4) 57.802,16.4 58.035,16.633 58.035,16.811 58.035,17.285 58.375,17.625 59.812,17.625 cw(c60.075,17.025) 60.338,17.625 60.426,17.625 60.455,17.654 60.457,17.657 cw(c60.95,17.225) 61.442,17.657 ccw(c61.516,17.725) 61.448,17.652 61.476,17.625 61.516,17.625 63.7,17.625 64.225,18.15 74.875,18.15 76.33,19.605 96.87,19.605 97.215,19.26 97.215,18.978 97.443,18.75 v1(97.55,18.75)
USBDN2_N: U29.2 U33.3 | length 48.1
  Top Layer w0.1: U33.3@57.4,15.5 57.325,15.575 57.325,16.775 57.575,17.025 v1(57.575,17.075) ; v1(98.975,18.75) 99.175,18.55 U29.2@99.175,18
  Bottom Layer w0.1: v1(57.575,17.075) 57.473,17.075 57.265,17.283 57.265,17.366 57.265,17.865 57.92,18.52 63.82,18.52 64.445,19.145 74.895,19.145 76.025,20.275 98.975,20.275 99.31,19.94 99.31,19.016 99.31,18.933 99.251,18.875 99.221,18.875 99.097,18.75 v1(98.975,18.75)
USBDN2_P: U29.1 U33.4 | length 48.8
  Top Layer w0.1: v1(56.725,17.075) 56.725,17.025 56.9,16.85 U33.4@56.9,15.5 ; U29.1@99.675,18 99.675,18.55 v1(99.875,18.75)
  Bottom Layer w0.1: v1(56.725,17.075) 56.827,17.075 57.035,17.283 57.035,17.461 57.035,17.96 57.825,18.75 63.725,18.75 64.35,19.375 74.8,19.375 75.93,20.505 99.07,20.505 99.54,20.035 99.54,19.111 99.54,18.933 99.599,18.875 99.629,18.875 99.753,18.75 v1(99.875,18.75)
USBDN3_N: U26.2 U33.6 | length 26.7
  Top Layer w0.1: U33.6@55.9,15.5 55.9,16.25 56,16.35 v1(56,16.4) ; v1(77.65,18.75) 77.85,18.55 U26.2@77.85,18
  Bottom Layer w0.1: v1(56,16.4) 56,16.352 55.765,16.117 55.765,16.034 55.765,15.925 55.915,15.775 62.925,15.775 64.65,17.5 77.8,17.5 77.985,17.685 77.985,18.484 77.985,18.567 77.926,18.625 77.896,18.625 77.772,18.75 v1(77.65,18.75)
USBDN3_P: U26.1 U33.7 | length 27.4
  Top Layer w0.1: v1(55.3,16.375) 55.3,16.35 55.4,16.25 U33.7@55.4,15.5 ; U26.1@78.35,18 78.35,18.55 v1(78.55,18.75)
  Bottom Layer w0.1: v1(55.3,16.375) 55.3,16.327 55.535,16.092 55.535,15.939 55.535,15.83 55.82,15.545 63.02,15.545 64.745,17.27 77.895,17.27 78.215,17.59 78.215,18.389 78.215,18.567 78.274,18.625 78.304,18.625 78.428,18.75 v1(78.55,18.75)
USBDN4_N: U27.2 U33.8 | length 32.7
  Top Layer w0.1: U33.8@54.9,15.5 54.83,15.57 54.83,16.78 v1(55.125,17.075) ; v1(79.975,18.75) 80.175,18.55 U27.2@80.175,18
  Bottom Layer w0.1: v1(55.125,17.075) 54.765,16.715 54.765,16.565 54.765,15.585 55.275,15.075 63.399,15.075 64.979,16.655 80.08,16.655 80.31,16.885 80.31,18.227 80.31,18.415 v1(79.975,18.75)
USBDN4_P: U27.1 U33.9 | length 33.4
  Top Layer w0.1: v1(54.175,17.075) 54.4,16.85 U33.9@54.4,15.5 ; U27.1@80.675,18 80.675,18.55 v1(80.875,18.75)
  Bottom Layer w0.1: v1(54.175,17.075) 54.535,16.715 54.535,16.47 54.535,15.49 55.18,14.845 63.494,14.845 65.074,16.425 80.175,16.425 80.54,16.79 80.54,18.132 80.54,18.415 v1(80.875,18.75)
uSD_DETECT: CN3.9 R46.2 R188.1 U10.1 | length 59
  Top Layer w0.1: R188.1@84.75,24.568 85.337,24.568 86.13,23.775 91.725,23.775 92.6,24.65 94.05,24.65 94.925,25.525 94.925,26.075 95.775,26.925 96.725,26.925 v1(101.425,31.625) ; v1(101.425,58.95) R46.2@109.9,58.95 109.913,58.937 U10.1@110.875,58.937 110.888,58.95 CN3.9@112.5,58.95
  Bottom Layer w0.1: v1(101.425,31.625) v1(101.425,58.95)
VBUS_MEAS: R129.1 R134.2 U21.13 | length 3.4
  Top Layer w0.1: U21.13@102.95,24.45 R129.1@104.925,24.45 R134.2@104.925,23.025
VBUSc: C160.2 C161.2 CN12.A4 CN12.A9 CN12.B4 CN12.B9 TP68.1 U25.7 U25.8 U34.1 | length 5.6
  Top Layer w0.2: v1(5.075,13.075) CN12.B4@6.21,13.075 ; v1(5.075,15.575) CN12.B9@6.21,15.575 ; CN12.A9@7.91,12.825 v1(8.825,12.825) ; CN12.A4@7.91,15.825 v1(8.825,15.825) ; U25.8@15.2,8.9 TP68.1@15.2,10.4
  other v1: 12.2,8.475 11.3,8.875 12.2,9.35 13.425,9.35 9.95,10.35 9.925,11.475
